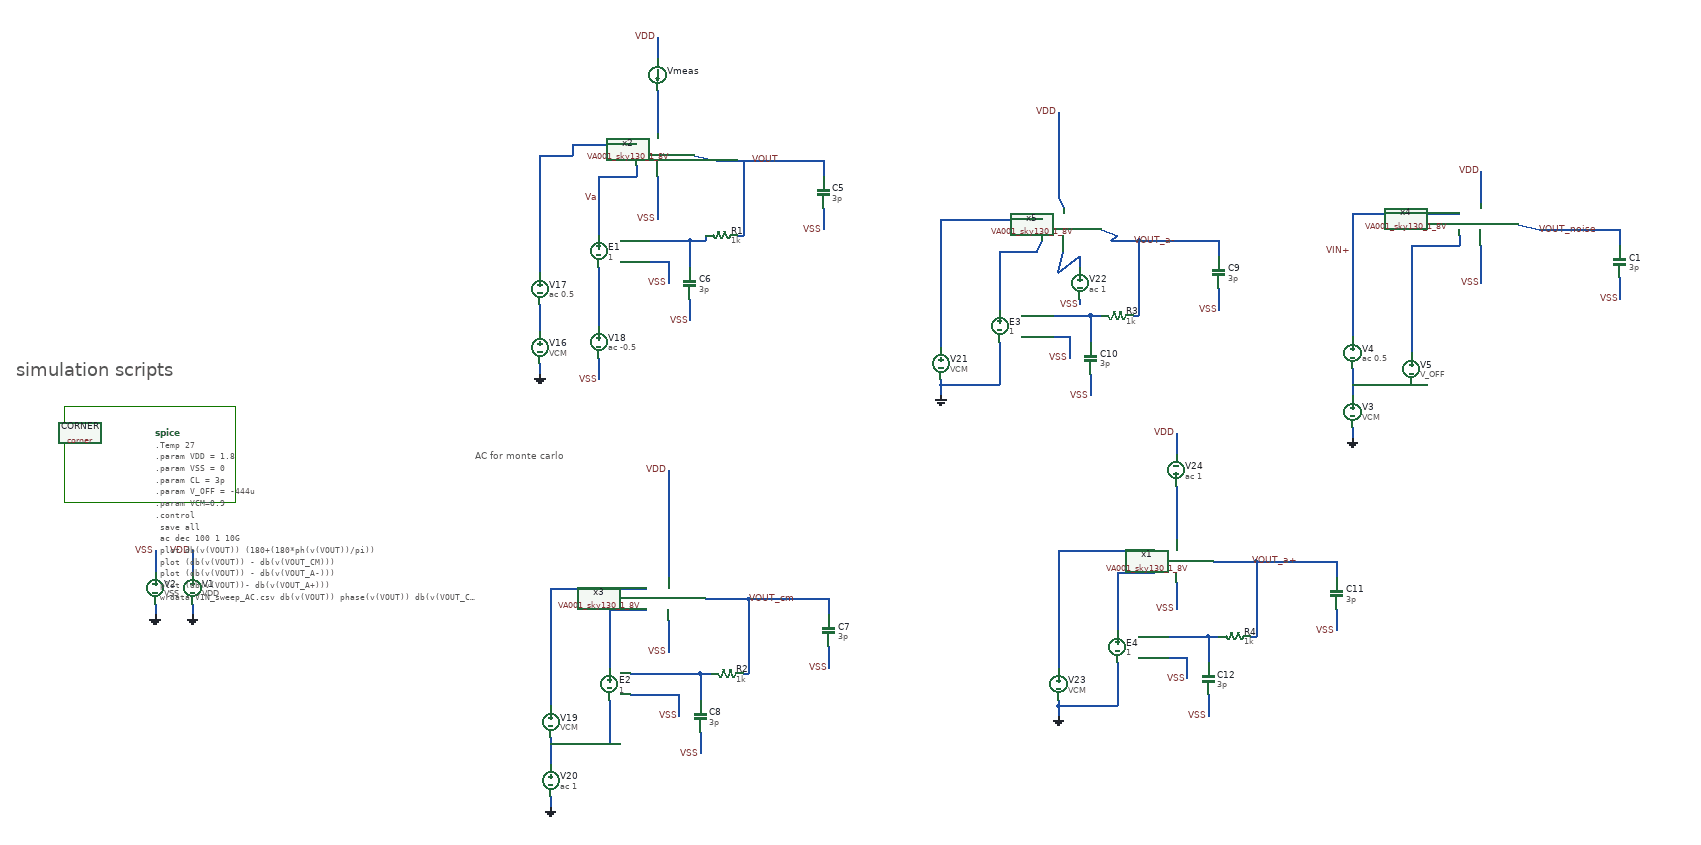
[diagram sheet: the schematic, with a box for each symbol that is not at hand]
v {xschem version=3.4.6 file_version=1.2}
G {}
K {}
V {}
S {}
E {}
L 4 -1420 -140 -1420 20 {}
L 4 -1420 20 -1100 20 {}
L 4 -1100 -160 -1100 20 {}
L 4 -1420 -160 -1100 -160 {}
L 4 -1420 -160 -1420 -140 {}
T {simulation scripts} -1510 -240 0 0 1 1 {}
T {AC for monte carlo} -650 -80 0 0 0.4 0.4 {}
N -1180 210 -1180 230 {
lab=GND}
N -1180 110 -1180 150 {
lab=VDD}
N -1250 210 -1250 230 {
lab=GND}
N -1250 110 -1250 150 {
lab=VSS}
N -310 -550 -310 -510 {
lab=VSS}
N -530 -350 -530 -300 {
lab=#net1}
N -310 -850 -310 -810 {
lab=VDD}
N -200 -620 -150 -620 {
lab=VOUT}
N -310 -750 -310 -690 {
lab=#net2}
N 0 -530 0 -490 {
lab=VSS}
N -160 -620 -20 -620 {lab=VOUT}
N -10 -620 0 -620 {lab=VOUT}
N 0 -620 0 -590 {lab=VOUT}
N -530 -630 -470 -630 {lab=#net3}
N -530 -240 -530 -220 {lab=GND}
N -530 -630 -530 -410 {lab=#net3}
N -420 -530 -420 -480 {lab=Va}
N -420 -590 -420 -530 {lab=Va}
N -420 -250 -420 -210 {
lab=VSS}
N -420 -420 -420 -390 {lab=#net4}
N -150 -620 -150 -480 {lab=VOUT}
N -290 -430 -290 -390 {
lab=VSS}
N -380 -430 -290 -430 {lab=VSS}
N -420 -340 -420 -310 {lab=#net4}
N -420 -390 -420 -340 {lab=#net4}
N -160 -480 -150 -480 {lab=VOUT}
N -250 -360 -250 -320 {
lab=VSS}
N -250 -470 -250 -420 {lab=#net5}
N -250 -470 -230 -470 {lab=#net5}
N -380 -470 -250 -470 {lab=#net5}
N -290 260 -290 300 {
lab=VSS}
N -510 460 -510 510 {
lab=#net6}
N -290 -40 -290 0 {
lab=VDD}
N -190 200 -140 200 {
lab=VOUT_cm}
N -290 60 -290 120 {
lab=VDD}
N 10 290 10 330 {
lab=VSS}
N 0 200 10 200 {lab=VOUT_cm}
N 10 200 10 230 {lab=VOUT_cm}
N -510 180 -450 180 {lab=#net7}
N -510 570 -510 590 {lab=GND}
N -510 180 -510 400 {lab=#net7}
N -400 280 -400 330 {lab=#net8}
N -400 220 -400 280 {lab=#net8}
N -140 200 -140 340 {lab=VOUT_cm}
N -270 380 -270 420 {
lab=VSS}
N -360 380 -270 380 {lab=VSS}
N -150 340 -140 340 {lab=VOUT_cm}
N -230 450 -230 490 {
lab=VSS}
N -230 340 -230 390 {lab=#net9}
N -230 340 -210 340 {lab=#net9}
N -360 340 -230 340 {lab=#net9}
N -400 390 -400 470 {lab=#net6}
N -510 470 -400 470 {lab=#net6}
N -140 200 0 200 {lab=VOUT_cm}
N 440 -710 440 -670 {
lab=VDD}
N 540 -470 590 -470 {
lab=VOUT_a-}
N 440 -610 440 -550 {
lab=VDD}
N 320 -510 410 -510 {lab=#net10}
N 740 -380 740 -340 {
lab=VSS}
N 730 -470 740 -470 {lab=VOUT_a-}
N 740 -470 740 -440 {lab=VOUT_a-}
N 220 -200 220 -180 {lab=GND}
N 220 -490 220 -270 {lab=#net10}
N 330 -390 330 -340 {lab=#net11}
N 330 -450 330 -390 {lab=#net11}
N 590 -470 590 -330 {lab=VOUT_a-}
N 460 -290 460 -250 {
lab=VSS}
N 370 -290 460 -290 {lab=VSS}
N 580 -330 590 -330 {lab=VOUT_a-}
N 500 -220 500 -180 {
lab=VSS}
N 500 -330 500 -280 {lab=#net12}
N 500 -330 520 -330 {lab=#net12}
N 370 -330 500 -330 {lab=#net12}
N 330 -280 330 -200 {lab=GND}
N 220 -200 330 -200 {lab=GND}
N 590 -470 730 -470 {lab=VOUT_a-}
N 220 -210 220 -200 {lab=GND}
N 480 -440 480 -420 {lab=#net13}
N 480 -360 480 -350 {lab=VSS}
N 660 -110 660 -70 {
lab=VDD}
N 760 130 810 130 {
lab=VOUT_a+}
N 660 -10 660 50 {
lab=#net14}
N 500 110 590 110 {lab=#net15}
N 960 220 960 260 {
lab=VSS}
N 950 130 960 130 {lab=VOUT_a+}
N 960 130 960 160 {lab=VOUT_a+}
N 440 110 500 110 {lab=#net15}
N 550 150 600 150 {lab=#net16}
N 440 400 440 420 {lab=GND}
N 440 110 440 330 {lab=#net15}
N 550 210 550 260 {lab=#net16}
N 550 150 550 210 {lab=#net16}
N 810 130 810 270 {lab=VOUT_a+}
N 680 310 680 350 {
lab=VSS}
N 590 310 680 310 {lab=VSS}
N 800 270 810 270 {lab=VOUT_a+}
N 720 380 720 420 {
lab=VSS}
N 720 270 720 320 {lab=#net17}
N 720 270 740 270 {lab=#net17}
N 590 270 720 270 {lab=#net17}
N 550 320 550 400 {lab=GND}
N 440 400 550 400 {lab=GND}
N 810 130 950 130 {lab=VOUT_a+}
N 440 390 440 400 {lab=GND}
N 660 190 660 210 {lab=VSS}
N 660 210 660 220 {lab=VSS}
N 440 -670 440 -610 {lab=VDD}
N -290 0 -290 60 {lab=VDD}
N -420 -590 -350 -590 {lab=Va}
N -470 -650 -350 -650 {lab=#net3}
N -470 -650 -470 -630 {lab=#net3}
N -220 -480 -220 -470 {lab=#net5}
N -230 -470 -220 -470 {lab=#net5}
N 220 -510 320 -510 {lab=#net10}
N 220 -510 220 -490 {lab=#net10}
N 330 -450 400 -450 {lab=#net11}
N 440 -410 480 -440 {lab=#net13}
N 540 -470 550 -480 {lab=VOUT_a-}
N 600 150 620 150 {lab=#net16}
N -400 220 -330 220 {lab=#net8}
N 990 -230 990 -180 {
lab=#net18}
N 990 -120 990 -100 {lab=GND}
N 990 -510 990 -290 {lab=VIN+}
N 990 -520 990 -510 {lab=VIN+}
N 990 -520 1190 -520 {lab=VIN+}
N 990 -200 1100 -200 {lab=#net18}
N 1100 -460 1100 -260 {lab=#net19}
N 1100 -460 1190 -460 {lab=#net19}
N 1230 -420 1230 -400 {lab=VSS}
N 1230 -400 1230 -390 {lab=VSS}
N 1230 -600 1230 -560 {
lab=VDD}
N 1490 -400 1490 -360 {
lab=VSS}
N 1480 -490 1490 -490 {lab=VOUT_noise}
N 1490 -490 1490 -460 {lab=VOUT_noise}
N 1340 -490 1480 -490 {lab=VOUT_noise}
N -20 -620 -10 -620 {lab=VOUT}
N -350 -610 -350 -590 {lab=Va}
N -310 -690 -310 -670 {lab=#net2}
N -240 -630 -200 -620 {lab=VOUT}
N -310 -590 -310 -550 {lab=VSS}
N -450 180 -330 180 {lab=#net7}
N -290 120 -290 160 {lab=VDD}
N -290 240 -290 260 {lab=VSS}
N -210 200 -190 200 {lab=VOUT_cm}
N -220 200 -210 200 {lab=VOUT_cm}
N 590 110 620 110 {lab=#net15}
N 660 170 660 190 {lab=VSS}
N 660 60 660 90 {lab=#net14}
N 660 50 660 60 {lab=#net14}
N 730 130 760 130 {lab=VOUT_a+}
N 1230 -560 1230 -540 {lab=VDD}
N 1300 -500 1340 -490 {lab=VOUT_noise}
N 1190 -480 1190 -460 {lab=#net19}
N 1230 -460 1230 -420 {lab=VSS}
N 400 -450 410 -470 {lab=#net11}
N 440 -410 450 -450 {lab=#net13}
N 520 -490 550 -480 {lab=VOUT_a-}
N 440 -550 450 -530 {lab=VDD}
C {devices/lab_pin.sym} -1180 110 0 0 {name=p6 sig_type=std_logic lab=VDD}
C {devices/vsource.sym} -1180 180 0 0 {name=V1 value="VDD"

}
C {devices/gnd.sym} -1180 230 0 0 {name=l3 lab=GND}
C {devices/vsource.sym} -1250 180 0 0 {name=V2 value="VSS"


}
C {devices/gnd.sym} -1250 230 0 0 {name=l1 lab=GND}
C {sky130_fd_pr/corner.sym} -1390 -110 0 0 {name=CORNER only_toplevel=true corner=tt}
C {devices/lab_pin.sym} -1250 110 0 0 {name=p8 sig_type=std_logic lab=VSS
}
C {devices/code.sym} -1250 -110 0 0 {name=spice only_toplevel=false
format="tcleval( @value )"
value="	
.Temp 27
.param VDD = 1.8
.param VSS = 0
.param CL = 3p
.param V_OFF = -444u
.param VCM=0.9


.control

	save all
	ac dec 100 1 10G
	plot db(v(VOUT)) (180+(180*ph(v(VOUT))/pi))
	plot (db(v(VOUT)) - db(v(VOUT_CM)))
	plot (db(v(VOUT)) - db(v(VOUT_A-)))
	plot (db(v(VOUT))- db(v(VOUT_A+)))	
	wrdata VIN_sweep_AC.csv db(v(VOUT)) phase(v(VOUT)) db(v(VOUT_CM)) db(v(VOUT_A-)) db(v(VOUT_A+))

	noise v(VOUT_noise,VSS) V4 dec 10 1 40000k
	print inoise_total 
	print onoise_total
	setplot noise1

	plot onoise_spectrum
	plot inoise_spectrum
	op
	print (0.9-V(VOUT))
	print v(VOUT_noise)

.endc



"}
C {devices/lab_pin.sym} -310 -510 0 0 {name=p23 sig_type=std_logic lab=VSS
}
C {devices/lab_pin.sym} -310 -850 0 0 {name=p24 sig_type=std_logic lab=VDD}
C {ammeter.sym} -310 -780 0 0 {name=Vmeas savecurrent=true}
C {capa.sym} 0 -560 0 0 {name=C5
m=1
value=3p
footprint=1206
device="ceramic capacitor"}
C {devices/lab_pin.sym} 0 -490 0 0 {name=p26 sig_type=std_logic lab=VSS
}
C {devices/vsource.sym} -530 -270 0 0 {name=V16 value= "VCM"}
C {devices/gnd.sym} -530 -220 0 0 {name=l7 lab=GND}
C {devices/vsource.sym} -530 -380 0 0 {name=V17 value= "ac 0.5"}
C {devices/lab_pin.sym} 990 -450 0 0 {name=p27 sig_type=std_logic lab=VIN+
}
C {devices/lab_pin.sym} -420 -210 0 0 {name=p28 sig_type=std_logic lab=VSS
}
C {devices/vsource.sym} -420 -280 0 0 {name=V18 value= "ac -0.5"}
C {vcvs.sym} -420 -450 0 1 {name=E1 value=1}
C {devices/lab_pin.sym} -290 -390 0 0 {name=p29 sig_type=std_logic lab=VSS
}
C {devices/lab_pin.sym} -420 -550 0 0 {name=p30 sig_type=std_logic lab=Va
}
C {res_ac.sym} -190 -480 1 0 {name=R1
value=1k
ac=1000000000000G
m=1}
C {capa.sym} -250 -390 0 0 {name=C6
m=1
value=3p
footprint=1206
device="ceramic capacitor"}
C {devices/lab_pin.sym} -250 -320 0 0 {name=p31 sig_type=std_logic lab=VSS
}
C {devices/lab_pin.sym} -290 300 0 0 {name=p32 sig_type=std_logic lab=VSS
}
C {devices/lab_pin.sym} -290 -40 0 0 {name=p33 sig_type=std_logic lab=VDD}
C {capa.sym} 10 260 0 0 {name=C7
m=1
value=3p
footprint=1206
device="ceramic capacitor"}
C {devices/lab_pin.sym} 10 330 0 0 {name=p34 sig_type=std_logic lab=VSS
}
C {devices/vsource.sym} -510 430 0 0 {name=V19 value= "VCM"}
C {devices/gnd.sym} -510 590 0 0 {name=l8 lab=GND}
C {devices/vsource.sym} -510 540 0 0 {name=V20 value= "ac 1"}
C {vcvs.sym} -400 360 0 1 {name=E2 value=1}
C {devices/lab_pin.sym} -270 420 0 0 {name=p35 sig_type=std_logic lab=VSS
}
C {res_ac.sym} -180 340 1 0 {name=R2
value=1k
ac=1000000000000G
m=1}
C {capa.sym} -230 420 0 0 {name=C8
m=1
value=3p
footprint=1206
device="ceramic capacitor"}
C {devices/lab_pin.sym} -230 490 0 0 {name=p36 sig_type=std_logic lab=VSS
}
C {devices/lab_pin.sym} 480 -350 0 0 {name=p38 sig_type=std_logic lab=VSS
}
C {devices/lab_pin.sym} 440 -710 0 0 {name=p39 sig_type=std_logic lab=VDD}
C {capa.sym} 740 -410 0 0 {name=C9
m=1
value=3p
footprint=1206
device="ceramic capacitor"}
C {devices/lab_pin.sym} 740 -340 0 0 {name=p40 sig_type=std_logic lab=VSS
}
C {devices/vsource.sym} 220 -240 0 0 {name=V21 value= "VCM"}
C {devices/gnd.sym} 220 -180 0 0 {name=l9 lab=GND}
C {vcvs.sym} 330 -310 0 1 {name=E3 value=1}
C {devices/lab_pin.sym} 460 -250 0 0 {name=p41 sig_type=std_logic lab=VSS
}
C {res_ac.sym} 550 -330 1 0 {name=R3
value=1k
ac=1000000000000G
m=1}
C {capa.sym} 500 -250 0 0 {name=C10
m=1
value=3p
footprint=1206
device="ceramic capacitor"}
C {devices/lab_pin.sym} 500 -180 0 0 {name=p42 sig_type=std_logic lab=VSS
}
C {devices/vsource.sym} 480 -390 0 0 {name=V22 value= "ac 1"}
C {devices/lab_pin.sym} 660 220 0 0 {name=p44 sig_type=std_logic lab=VSS
}
C {devices/lab_pin.sym} 660 -110 0 0 {name=p45 sig_type=std_logic lab=VDD}
C {capa.sym} 960 190 0 0 {name=C11
m=1
value=3p
footprint=1206
device="ceramic capacitor"}
C {devices/lab_pin.sym} 960 260 0 0 {name=p46 sig_type=std_logic lab=VSS
}
C {devices/vsource.sym} 440 360 0 0 {name=V23 value= "VCM"}
C {devices/gnd.sym} 440 420 0 0 {name=l10 lab=GND}
C {vcvs.sym} 550 290 0 1 {name=E4 value=1}
C {devices/lab_pin.sym} 680 350 0 0 {name=p47 sig_type=std_logic lab=VSS
}
C {res_ac.sym} 770 270 1 0 {name=R4
value=1k
ac=1000000000000G
m=1}
C {capa.sym} 720 350 0 0 {name=C12
m=1
value=3p
footprint=1206
device="ceramic capacitor"}
C {devices/lab_pin.sym} 720 420 0 0 {name=p48 sig_type=std_logic lab=VSS
}
C {devices/vsource.sym} 660 -40 2 0 {name=V24 value= "ac 1"}
C {devices/lab_pin.sym} 890 130 1 0 {name=p49 sig_type=std_logic lab=VOUT_a+

}
C {devices/lab_pin.sym} 660 -470 1 0 {name=p43 sig_type=std_logic lab=VOUT_a-

}
C {devices/lab_pin.sym} -50 200 1 0 {name=p37 sig_type=std_logic lab=VOUT_cm

}
C {devices/lab_pin.sym} -80 -620 1 0 {name=p25 sig_type=std_logic lab=VOUT
}
C {devices/vsource.sym} 990 -150 0 0 {name=V3 value= "VCM"}
C {devices/gnd.sym} 990 -100 0 0 {name=l2 lab=GND}
C {devices/vsource.sym} 990 -260 0 0 {name=V4 value= "ac 0.5"}
C {devices/vsource.sym} 1100 -230 0 0 {name=V5 value= "V_OFF"}
C {devices/lab_pin.sym} 1230 -390 0 0 {name=p2 sig_type=std_logic lab=VSS
}
C {devices/lab_pin.sym} 1230 -600 0 0 {name=p3 sig_type=std_logic lab=VDD}
C {capa.sym} 1490 -430 0 0 {name=C1
m=1
value=3p
footprint=1206
device="ceramic capacitor"}
C {devices/lab_pin.sym} 1490 -360 0 0 {name=p4 sig_type=std_logic lab=VSS
}
C {devices/lab_pin.sym} 1450 -490 1 0 {name=p5 sig_type=std_logic lab=VOUT_noise

}
C {Sky130A/single ended amplifiers/VA001_sky130_1_8V.sym} -310 -630 0 0 {name=x2}
C {Sky130A/single ended amplifiers/VA001_sky130_1_8V.sym} -290 200 0 0 {name=x3}
C {Sky130A/single ended amplifiers/VA001_sky130_1_8V.sym} 660 130 0 0 {name=x1}
C {Sky130A/single ended amplifiers/VA001_sky130_1_8V.sym} 1230 -500 0 0 {name=x4}
C {Sky130A/single ended amplifiers/VA001_sky130_1_8V.sym} 450 -490 0 0 {name=x5}
